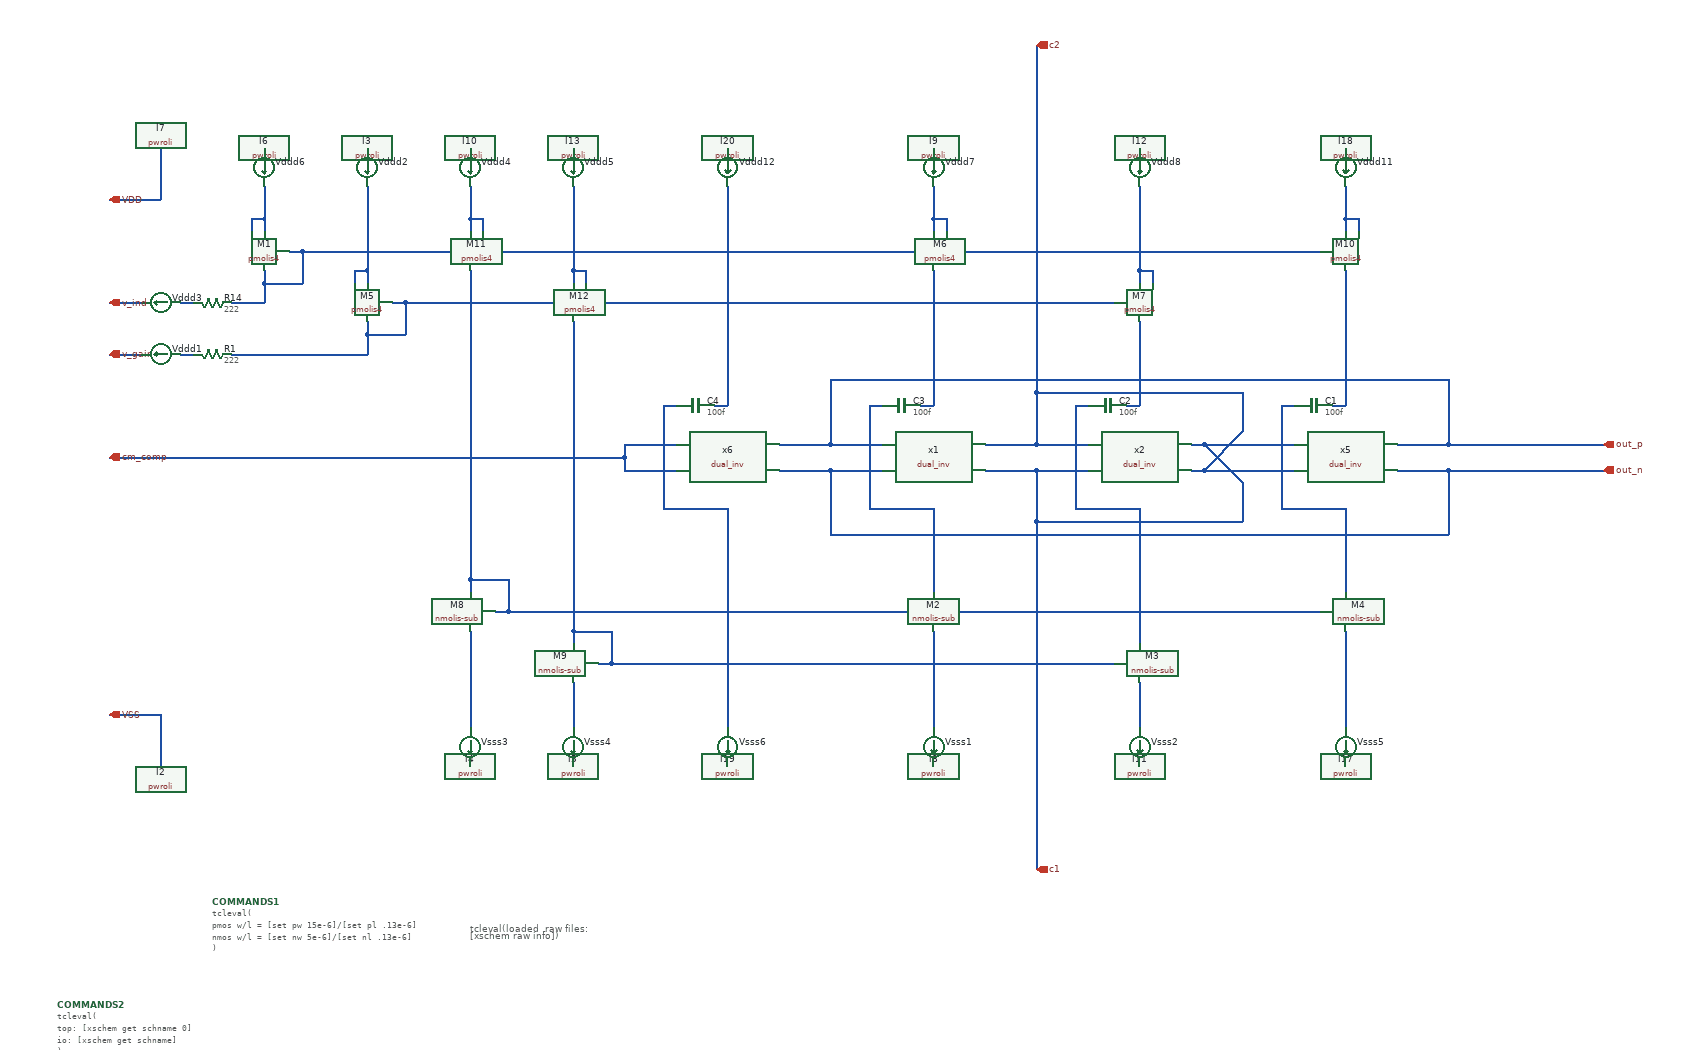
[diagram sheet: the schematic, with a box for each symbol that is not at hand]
v {xschem version=3.4.7RC file_version=1.2
*
* This file is part of XSCHEM,
* a schematic capture and Spice/Vhdl/Verilog netlisting tool for circuit
* simulation.
* Copyright (C) 1998-2023 Stefan Frederik Schippers
*
* This program is free software; you can redistribute it and/or modify
* it under the terms of the GNU General Public License as published by
* the Free Software Foundation; either version 2 of the License, or
* (at your option) any later version.
*
* This program is distributed in the hope that it will be useful,
* but WITHOUT ANY WARRANTY; without even the implied warranty of
* MERCHANTABILITY or FITNESS FOR A PARTICULAR PURPOSE.  See the
* GNU General Public License for more details.
*
* You should have received a copy of the GNU General Public License
* along with this program; if not, write to the Free Software
* Foundation, Inc., 51 Franklin Street, Fifth Floor, Boston, MA 02110-1301 USA
}
G {}
K {}
V {}
S {}
E {}
T {tcleval(loaded .raw files: 
[xschem raw info])} 800 -320 0 0 0.3 0.3 {floater=true layer=16}
N 240 -640 320 -640 {
lab=VSS}
N 320 -640 320 -560 {
lab=VSS}
N 480 -1410 480 -1390 {lab=#net1}
N 460 -1410 460 -1390 {lab=#net1}
N 240 -1280 290 -1280 {lab=v_ind}
N 480 -1310 540 -1310 {lab=#net2}
N 480 -1330 480 -1310 {lab=#net2}
N 540 -1360 540 -1310 {lab=#net2}
N 520 -1360 540 -1360 {lab=#net2}
N 460 -1410 480 -1410 {lab=#net1}
N 480 -1460 480 -1410 {lab=#net1}
N 240 -1440 320 -1440 {
lab=VDD}
N 320 -1520 320 -1440 {
lab=VDD}
N 1520 -1410 1520 -1390 {lab=#net3}
N 1540 -1410 1540 -1390 {lab=#net3}
N 1520 -1410 1540 -1410 {lab=#net3}
N 1520 -1460 1520 -1410 {lab=#net3}
N 1840 -1330 1840 -1310 {lab=#net4}
N 1860 -1330 1860 -1310 {lab=#net4}
N 1840 -1330 1860 -1330 {lab=#net4}
N 1840 -1460 1840 -1330 {lab=#net4}
N 1680 -1060 1760 -1060 {lab=c2}
N 1680 -1020 1760 -1020 {lab=c1}
N 1680 -1140 1680 -1060 {lab=c2}
N 1600 -1060 1680 -1060 {lab=c2}
N 1600 -1020 1680 -1020 {lab=c1}
N 2160 -1410 2160 -1390 {lab=#net5}
N 2180 -1410 2180 -1390 {lab=#net5}
N 2160 -1410 2180 -1410 {lab=#net5}
N 2160 -1460 2160 -1410 {lab=#net5}
N 1200 -1460 1200 -1120 {lab=#net6}
N 2240 -1060 2320 -1060 {lab=out_p}
N 2320 -1160 2320 -1060 {lab=out_p}
N 2240 -1020 2320 -1020 {lab=out_n}
N 2320 -1020 2320 -920 {lab=out_n}
N 1040 -1060 1120 -1060 {lab=cm_comp}
N 1040 -1040 1040 -1020 {lab=cm_comp}
N 1040 -1020 1120 -1020 {lab=cm_comp}
N 240 -1040 1040 -1040 {lab=cm_comp}
N 1040 -1060 1040 -1040 {lab=cm_comp}
N 2320 -1020 2560 -1020 {lab=out_n}
N 2320 -1060 2560 -1060 {lab=out_p}
N 1360 -1160 2320 -1160 {lab=out_p}
N 1360 -1160 1360 -1060 {lab=out_p}
N 1360 -1060 1440 -1060 {lab=out_p}
N 1360 -1020 1360 -920 {lab=out_n}
N 1360 -1020 1440 -1020 {lab=out_n}
N 1360 -920 2320 -920 {lab=out_n}
N 1280 -1020 1360 -1020 {lab=out_n}
N 1280 -1060 1360 -1060 {lab=out_p}
N 350 -1280 370 -1280 {lab=#net7}
N 430 -1280 480 -1280 {lab=#net2}
N 480 -1310 480 -1280 {lab=#net2}
N 1680 -1140 2000 -1140 {lab=c2}
N 1680 -1680 1680 -1140 {lab=c2}
N 2000 -1140 2000 -1080 {lab=c2}
N 1940 -1020 2000 -1080 {lab=c2}
N 1940 -1020 2080 -1020 {lab=c2}
N 1940 -1060 2000 -1000 {lab=c1}
N 1940 -1060 2080 -1060 {lab=c1}
N 2000 -1000 2000 -940 {lab=c1}
N 1680 -940 2000 -940 {lab=c1}
N 1680 -1020 1680 -940 {lab=c1}
N 1840 -1250 1840 -1120 {lab=#net8}
N 2140 -1120 2160 -1120 {lab=#net9}
N 2060 -1120 2080 -1120 {lab=#net10}
N 2060 -1120 2060 -960 {lab=#net10}
N 2060 -960 2160 -960 {lab=#net10}
N 1820 -1120 1840 -1120 {lab=#net8}
N 1740 -1120 1760 -1120 {lab=#net11}
N 1740 -1120 1740 -960 {lab=#net11}
N 1740 -960 1840 -960 {lab=#net11}
N 1500 -1120 1520 -1120 {lab=#net12}
N 1420 -1120 1440 -1120 {lab=#net13}
N 1420 -1120 1420 -960 {lab=#net13}
N 1420 -960 1520 -960 {lab=#net13}
N 1180 -1120 1200 -1120 {lab=#net6}
N 1100 -1120 1120 -1120 {lab=#net14}
N 1100 -1120 1100 -960 {lab=#net14}
N 1100 -960 1200 -960 {lab=#net14}
N 1200 -960 1200 -620 {lab=#net14}
N 1520 -770 1520 -620 {lab=#net15}
N 1840 -960 1840 -750 {lab=#net11}
N 1840 -690 1840 -620 {lab=#net16}
N 2160 -770 2160 -620 {lab=#net17}
N 1680 -940 1680 -400 {lab=c1}
N 640 -1330 640 -1310 {lab=#net18}
N 620 -1330 620 -1310 {lab=#net18}
N 640 -1230 700 -1230 {lab=#net19}
N 640 -1250 640 -1230 {lab=#net19}
N 700 -1280 700 -1230 {lab=#net19}
N 680 -1280 700 -1280 {lab=#net19}
N 620 -1330 640 -1330 {lab=#net18}
N 700 -1280 1800 -1280 {lab=#net19}
N 350 -1200 370 -1200 {lab=#net20}
N 430 -1200 640 -1200 {lab=#net19}
N 640 -1230 640 -1200 {lab=#net19}
N 640 -1460 640 -1330 {lab=#net18}
N 240 -1200 290 -1200 {lab=v_gain}
N 540 -1360 2120 -1360 {lab=#net2}
N 960 -690 960 -620 {lab=#net21}
N 800 -770 800 -620 {lab=#net22}
N 800 -1410 800 -1390 {lab=#net23}
N 820 -1410 820 -1390 {lab=#net23}
N 800 -1410 820 -1410 {lab=#net23}
N 800 -1460 800 -1410 {lab=#net23}
N 960 -1330 960 -1310 {lab=#net24}
N 980 -1330 980 -1310 {lab=#net24}
N 960 -1330 980 -1330 {lab=#net24}
N 960 -1460 960 -1330 {lab=#net24}
N 800 -850 800 -830 {lab=#net25}
N 960 -770 960 -750 {lab=#net26}
N 860 -800 2120 -800 {lab=#net25}
N 1020 -720 1800 -720 {lab=#net26}
N 960 -770 1020 -770 {lab=#net26}
N 960 -1250 960 -770 {lab=#net26}
N 1020 -770 1020 -720 {lab=#net26}
N 1000 -720 1020 -720 {lab=#net26}
N 860 -850 860 -800 {lab=#net25}
N 840 -800 860 -800 {lab=#net25}
N 800 -850 860 -850 {lab=#net25}
N 800 -1330 800 -850 {lab=#net25}
N 1520 -1330 1520 -1120 {lab=#net12}
N 2160 -1330 2160 -1120 {lab=#net9}
N 1520 -960 1520 -830 {lab=#net13}
N 2160 -960 2160 -830 {lab=#net10}
N 1920 -1020 1940 -1020 {lab=c2}
N 1920 -1060 1940 -1060 {lab=c1}
C {title.sym} 160 -30 0 0 {name=l1 author="om"  net_name=true}
C {ammeter.sym} 320 -1280 1 1 {name=Vddd3
savecurrent=true
lvs_ignore=short}
C {iopin.sym} 240 -640 0 1 {name=p8 lab=VSS

}
C {pwroli.sym} 320 -560 0 0 {name=l2 lab=VSS}
C {iopin.sym} 240 -1280 0 1 {name=p9 lab=v_ind}
C {simulator_commands_shown.sym} 160 -190 0 0 {name=COMMANDS2
simulator=none
only_toplevel=false 

value="tcleval(
top: [xschem get schname 0]
io:  [xschem get schname]

)"}
C {simulator_commands_shown.sym} 400 -350 0 0 {name=COMMANDS1
simulator=none
only_toplevel=true 

value="tcleval(

pmos w/l = [set pw 15e-6]/[set pl .13e-6]
nmos w/l = [set nw 5e-6]/[set nl .13e-6]

)"}
C {launcher.sym} 460 -440 0 0 {name=h2
descr="load OP from TOP"
tclcommand="
	xschem annotate_op $\{netlist_dir\}/[file rootname [file tail [xschem get schname 0]]].raw 0;
	xschem load_raw $\{netlist_dir\}/[file rootname [file tail [xschem get schname 0]]]_dc.raw 0;

"
}
C {pmolis4.sym} 500 -1360 0 1 {name=M1
w=10u
l=1u
ng=1
m=1
substrate=VDD
model=sg13_lv_pmos
spiceprefix=X
w0=10u
l0=.13u
rfmode="tcleval($mos_rf_mode)"}
C {pwroli.sym} 480 -1520 2 0 {name=l6 lab=VDD
}
C {ammeter.sym} 480 -1490 0 0 {name=Vddd6
savecurrent=true
lvs_ignore=short}
C {iopin.sym} 240 -1440 0 1 {name=p6 lab=VDD}
C {pwroli.sym} 320 -1520 2 0 {name=l7 lab=VDD
}
C {res.sym} 400 -1280 1 0 {name=R14
value=222
footprint=1206
device=resistor
m=1}
C {tcleval([xschem get current_dirname]/dual_inv.sym} 1520 -1040 0 1 {name=x1
nw="tcleval([string map \{\{$\} \{\}\} [ev \{$nw\}]])"
nl="tcleval([string map \{\{$\} \{\}\} [ev \{$nl\}]])"
pw="tcleval([string map \{\{$\} \{\}\} [ev \{$pw\}]])"
pl="tcleval([string map \{\{$\} \{\}\} [ev \{$pl\}]])"}
C {pwroli.sym} 1520 -560 0 1 {name=l8 lab=VSS}
C {ammeter.sym} 1520 -590 0 1 {name=Vsss1 
savecurrent=true
lvs_ignore=short}
C {pmolis4.sym} 1500 -1360 0 0 {name=M6
w=30u
l=1u
ng=1
m=1
substrate=VDD
model=sg13_lv_pmos
spiceprefix=X
w0=10u
l0=.13u
rfmode="tcleval($mos_rf_mode)"}
C {pwroli.sym} 1520 -1520 2 0 {name=l9 lab=VDD
}
C {ammeter.sym} 1520 -1490 0 0 {name=Vddd7
savecurrent=true
lvs_ignore=short}
C {tcleval([xschem get current_dirname]/dual_inv.sym} 1840 -1040 0 0 {name=x2
nw="tcleval([string map \{\{$\} \{\}\} [ev \{1 * $nw\}]])"
nl="tcleval([string map \{\{$\} \{\}\} [ev \{$nl\}]])"
pw="tcleval([string map \{\{$\} \{\}\} [ev \{1 * $pw\}]])"
pl="tcleval([string map \{\{$\} \{\}\} [ev \{$pl\}]])"}
C {pwroli.sym} 1840 -560 0 1 {name=l11 lab=VSS}
C {ammeter.sym} 1840 -590 0 1 {name=Vsss2 
savecurrent=true
lvs_ignore=short}
C {pmolis4.sym} 1820 -1280 0 0 {name=M7
w=30u
l=1u
ng=1
m=1
substrate=VDD
model=sg13_lv_pmos
spiceprefix=X
w0=10u
l0=.13u
rfmode="tcleval($mos_rf_mode)"}
C {pwroli.sym} 1840 -1520 2 0 {name=l12 lab=VDD
}
C {ammeter.sym} 1840 -1490 0 0 {name=Vddd8
savecurrent=true
lvs_ignore=short}
C {iopin.sym} 1680 -400 3 1 {name=p7 lab=c1}
C {iopin.sym} 1680 -1680 1 1 {name=p10 lab=c2}
C {tcleval([xschem get current_dirname]/dual_inv.sym} 2160 -1040 0 1 {name=x5
nw="tcleval([string map \{\{$\} \{\}\} [ev \{$nw\}]])"
nl="tcleval([string map \{\{$\} \{\}\} [ev \{$nl\}]])"
pw="tcleval([string map \{\{$\} \{\}\} [ev \{$pw\}]])"
pl="tcleval([string map \{\{$\} \{\}\} [ev \{$pl\}]])"}
C {pwroli.sym} 2160 -560 0 0 {name=l17 lab=VSS}
C {ammeter.sym} 2160 -590 0 0 {name=Vsss5 
savecurrent=true
lvs_ignore=short}
C {pmolis4.sym} 2140 -1360 0 0 {name=M10
w=30u
l=1u
ng=1
m=1
substrate=VDD
model=sg13_lv_pmos
spiceprefix=X
w0=10u
l0=.13u
rfmode="tcleval($mos_rf_mode)"}
C {pwroli.sym} 2160 -1520 2 1 {name=l18 lab=VDD
}
C {ammeter.sym} 2160 -1490 0 1 {name=Vddd11
savecurrent=true
lvs_ignore=short}
C {tcleval([xschem get current_dirname]/dual_inv.sym} 1200 -1040 0 0 {name=x6
nw="tcleval([string map \{\{$\} \{\}\} [ev \{.3 * $nw\}]])"
nl="tcleval([string map \{\{$\} \{\}\} [ev \{$nl\}]])"
pw="tcleval([string map \{\{$\} \{\}\} [ev \{.3 * $pw\}]])"
pl="tcleval([string map \{\{$\} \{\}\} [ev \{$pl\}]])"}
C {pwroli.sym} 1200 -560 0 0 {name=l19 lab=VSS}
C {ammeter.sym} 1200 -590 0 0 {name=Vsss6 
savecurrent=true
lvs_ignore=short}
C {pwroli.sym} 1200 -1520 2 1 {name=l20 lab=VDD
}
C {ammeter.sym} 1200 -1490 0 1 {name=Vddd12
savecurrent=true
lvs_ignore=short}
C {iopin.sym} 2560 -1060 2 1 {name=p11 lab=out_p}
C {iopin.sym} 240 -1040 0 1 {name=p12 lab=cm_comp}
C {iopin.sym} 2560 -1020 2 1 {name=p13 lab=out_n}
C {capa.sym} 2110 -1120 1 0 {name=C1
m=1
value=100f
footprint=1206
device="ceramic capacitor"}
C {capa.sym} 1790 -1120 1 0 {name=C2
m=1
value=100f
footprint=1206
device="ceramic capacitor"}
C {capa.sym} 1470 -1120 1 0 {name=C3
m=1
value=100f
footprint=1206
device="ceramic capacitor"}
C {capa.sym} 1150 -1120 1 0 {name=C4
m=1
value=100f
footprint=1206
device="ceramic capacitor"}
C {iopin.sym} 240 -1200 0 1 {name=p1 lab=v_gain}
C {nmolis-sub.sym} 1500 -800 0 0 {name=M2
w=10u
l=1u
ng=1
m=1

model=sg13_lv_nmos
spiceprefix=X
w0=3u
l0=0.13u
rfmode="tcleval($mos_rf_mode)"}
C {nmolis-sub.sym} 1820 -720 0 0 {name=M3
w=10u
l=1u
ng=1
m=1

model=sg13_lv_nmos
spiceprefix=X
w0=3u
l0=0.13u
rfmode="tcleval($mos_rf_mode)"}
C {nmolis-sub.sym} 2140 -800 0 0 {name=M4
w=10u
l=1u
ng=1
m=1

model=sg13_lv_nmos
spiceprefix=X
w0=3u
l0=0.13u
rfmode="tcleval($mos_rf_mode)"}
C {ammeter.sym} 320 -1200 1 1 {name=Vddd1
savecurrent=true
lvs_ignore=short}
C {pmolis4.sym} 660 -1280 0 1 {name=M5
w=10u
l=1u
ng=1
m=1
substrate=VDD
model=sg13_lv_pmos
spiceprefix=X
w0=10u
l0=.13u
rfmode="tcleval($mos_rf_mode)"}
C {res.sym} 400 -1200 1 0 {name=R1
value=222
footprint=1206
device=resistor
m=1}
C {pwroli.sym} 640 -1520 2 0 {name=l3 lab=VDD
}
C {ammeter.sym} 640 -1490 0 0 {name=Vddd2
savecurrent=true
lvs_ignore=short}
C {nmolis-sub.sym} 820 -800 0 1 {name=M8
w=10u
l=1u
ng=1
m=1

model=sg13_lv_nmos
spiceprefix=X
w0=3u
l0=0.13u
rfmode="tcleval($mos_rf_mode)"}
C {nmolis-sub.sym} 980 -720 0 1 {name=M9
w=10u
l=1u
ng=1
m=1

model=sg13_lv_nmos
spiceprefix=X
w0=3u
l0=0.13u
rfmode="tcleval($mos_rf_mode)"}
C {pwroli.sym} 800 -560 0 0 {name=l4 lab=VSS}
C {ammeter.sym} 800 -590 0 0 {name=Vsss3 
savecurrent=true
lvs_ignore=short}
C {pwroli.sym} 960 -560 0 0 {name=l5 lab=VSS}
C {ammeter.sym} 960 -590 0 0 {name=Vsss4 
savecurrent=true
lvs_ignore=short}
C {pmolis4.sym} 780 -1360 0 0 {name=M11
w=10u
l=1u
ng=1
m=1
substrate=VDD
model=sg13_lv_pmos
spiceprefix=X
w0=10u
l0=.13u
rfmode="tcleval($mos_rf_mode)"}
C {pwroli.sym} 800 -1520 2 0 {name=l10 lab=VDD
}
C {ammeter.sym} 800 -1490 0 0 {name=Vddd4
savecurrent=true
lvs_ignore=short}
C {pmolis4.sym} 940 -1280 0 0 {name=M12
w=10u
l=1u
ng=1
m=1
substrate=VDD
model=sg13_lv_pmos
spiceprefix=X
w0=10u
l0=.13u
rfmode="tcleval($mos_rf_mode)"}
C {pwroli.sym} 960 -1520 2 0 {name=l13 lab=VDD
}
C {ammeter.sym} 960 -1490 0 0 {name=Vddd5
savecurrent=true
lvs_ignore=short}
C {ngspice_probe.sym} 570 -1360 0 0 {name=r32}
C {ngspice_probe.sym} 570 -1200 0 0 {name=r2}
C {ngspice_probe.sym} 890 -800 0 0 {name=r3}
C {ngspice_probe.sym} 1050 -720 0 0 {name=r4}
C {ngspice_probe.sym} 1050 -1360 0 0 {name=r5}
C {ngspice_probe.sym} 1050 -1280 0 0 {name=r6}
C {ngspice_probe.sym} 850 -1040 0 0 {name=r7}
C {ngspice_probe.sym} 1520 -1200 0 0 {name=r8}
C {ngspice_probe.sym} 1840 -1210 0 0 {name=r9}
C {ngspice_probe.sym} 1840 -830 0 0 {name=r10}
C {ngspice_probe.sym} 1520 -880 0 0 {name=r11}
C {ngspice_probe.sym} 1400 -920 0 0 {name=r12}
C {ngspice_probe.sym} 1400 -1160 0 0 {name=r13}
C {ngspice_probe.sym} 1040 -1020 0 0 {name=r15}
C {ngspice_probe.sym} 1290 -1020 0 0 {name=r16}
C {ngspice_probe.sym} 1290 -1060 0 0 {name=r17}
C {ngspice_probe.sym} 1610 -1020 0 0 {name=r18}
C {ngspice_probe.sym} 1610 -1060 0 0 {name=r19}
C {ngspice_probe.sym} 2000 -1020 0 0 {name=r20}
C {ngspice_probe.sym} 2000 -1060 0 0 {name=r21}
C {ngspice_probe.sym} 2250 -1020 0 0 {name=r22}
C {ngspice_probe.sym} 2250 -1060 0 0 {name=r23}
C {ngspice_probe.sym} 1520 -1430 0 0 {name=r24}
C {launcher.sym} 460 -480 0 0 {name=h1
descr="write LVS netlist"
tclcommand="
	xschem set netlist_type spice
        xschem set format lvs_format
	set last_local_netlist_dir $local_netlist_dir
	#set local_netlist_dir 0
	xschem netlist [xschem get current_name].cdl
	set local_netlist_dir $last_local_netlist_dir
        #xschem set format \{\}
"
}
